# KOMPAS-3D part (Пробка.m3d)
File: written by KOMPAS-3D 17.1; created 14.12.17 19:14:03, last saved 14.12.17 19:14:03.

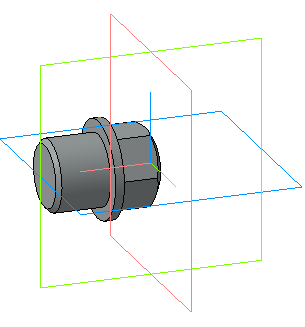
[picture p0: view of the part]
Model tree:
1. Операция без истории:1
